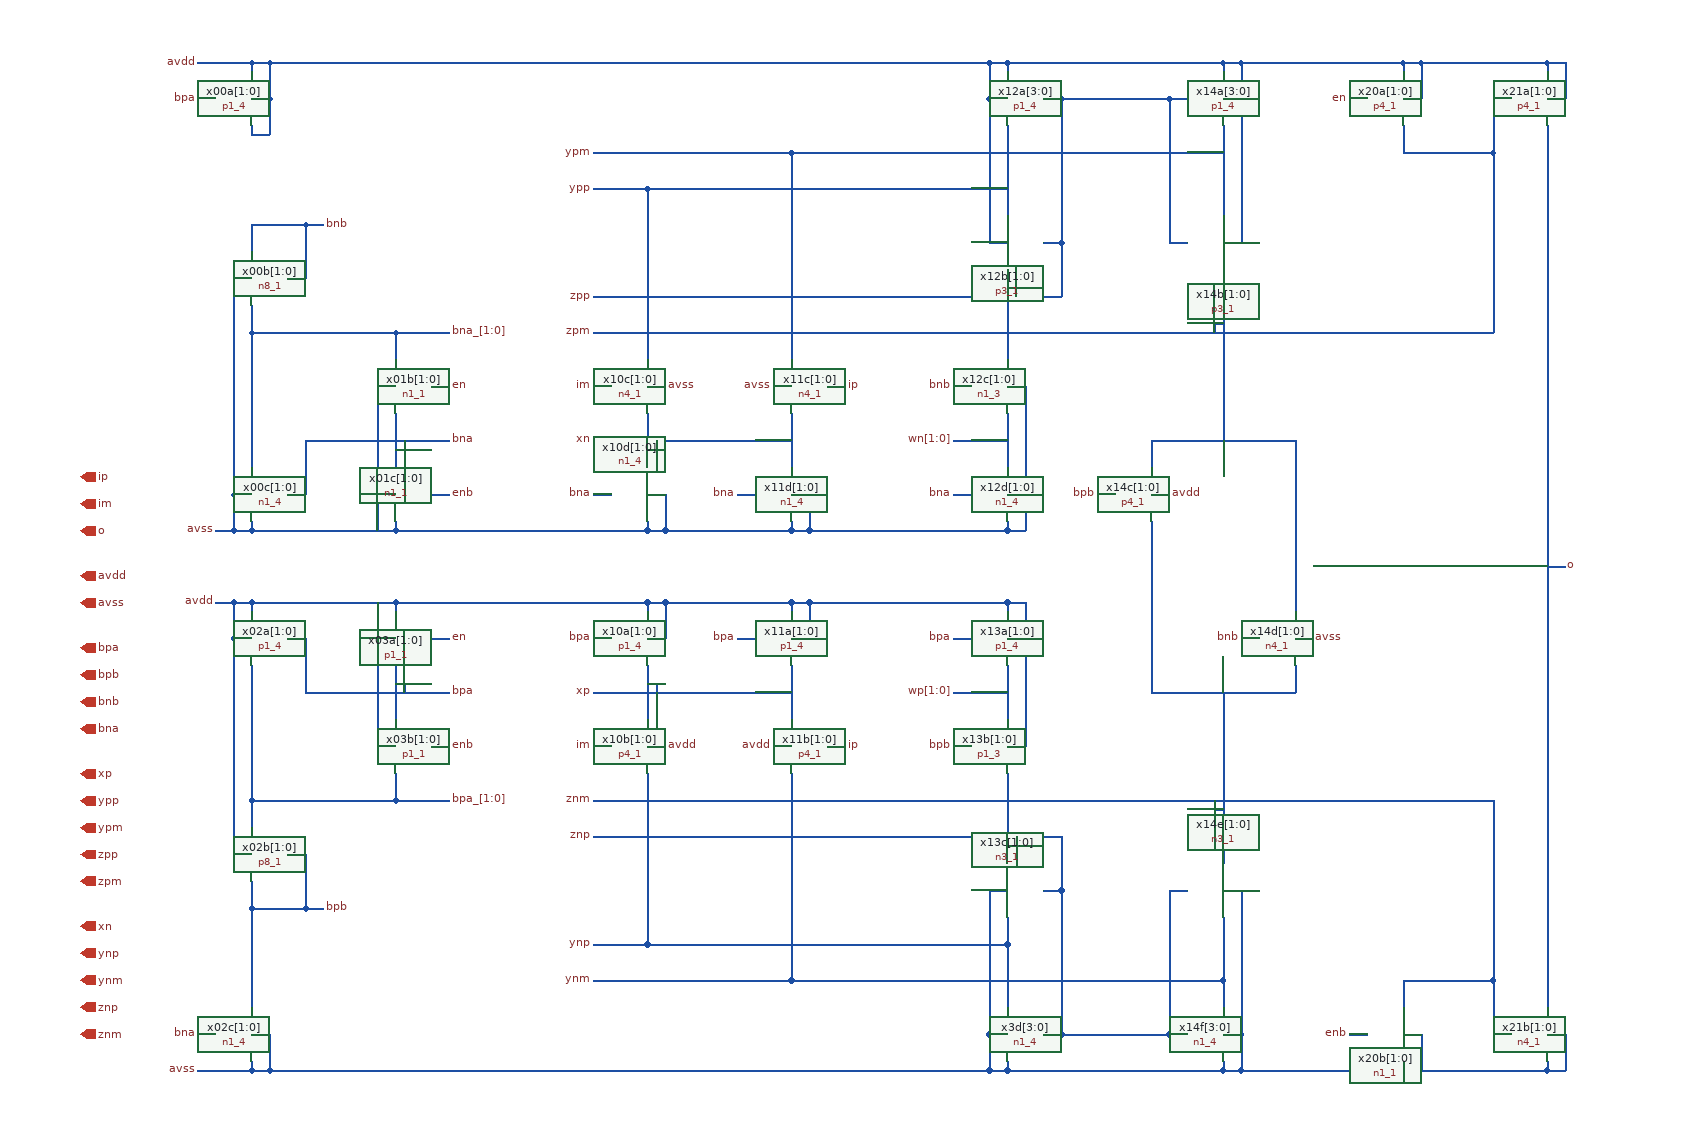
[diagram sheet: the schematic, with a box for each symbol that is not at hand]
v {xschem version=2.9.9 file_version=1.2 }
G {}
K {}
V {}
S {}
E {}
N 220 -760 240 -760 { lab=avss}
N 220 -760 220 -720 { lab=avss}
N 220 -720 240 -720 { lab=avss}
N 240 -730 240 -720 { lab=avss}
N 220 -1000 240 -1000 { lab=avss}
N 240 -1060 240 -1030 { lab=bnb}
N 240 -1060 300 -1060 { lab=bnb}
N 300 -1060 300 -1000 { lab=bnb}
N 280 -1000 300 -1000 { lab=bnb}
N 240 -130 240 -120 { lab=avss}
N 240 -300 300 -300 { lab=bpb}
N 300 -360 300 -300 { lab=bpb}
N 280 -360 300 -360 { lab=bpb}
N 240 -330 240 -300 { lab=bpb}
N 280 -600 300 -600 { lab=bpa}
N 220 -600 240 -600 { lab=avdd}
N 220 -640 220 -600 { lab=avdd}
N 220 -640 240 -640 { lab=avdd}
N 240 -640 240 -630 { lab=avdd}
N 240 -160 260 -160 { lab=avss}
N 260 -160 260 -120 { lab=avss}
N 240 -120 260 -120 { lab=avss}
N 300 -1060 320 -1060 { lab=bnb}
N 300 -300 320 -300 { lab=bpb}
N 220 -360 240 -360 { lab=avdd}
N 200 -640 220 -640 { lab=avdd}
N 200 -720 220 -720 { lab=avss}
N 840 -600 860 -600 { lab=avdd}
N 860 -640 860 -600 { lab=avdd}
N 840 -640 860 -640 { lab=avdd}
N 840 -640 840 -630 { lab=avdd}
N 1140 -380 1140 -320 { lab=znp}
N 1120 -160 1140 -160 { lab=znp}
N 1140 -320 1140 -200 { lab=znp}
N 1120 -320 1140 -320 { lab=znp}
N 1080 -130 1080 -120 { lab=avss}
N 1060 -160 1080 -160 { lab=avss}
N 1060 -160 1060 -120 { lab=avss}
N 1060 -120 1080 -120 { lab=avss}
N 1060 -320 1080 -320 { lab=avss}
N 1140 -200 1140 -160 { lab=znp}
N 1060 -320 1060 -160 { lab=avss}
N 1080 -570 1080 -510 { lab=wp[1:0]}
N 1260 -320 1280 -320 { lab=znp}
N 1320 -320 1340 -320 { lab=avss}
N 1320 -160 1340 -160 { lab=avss}
N 1340 -160 1340 -120 { lab=avss}
N 1320 -120 1340 -120 { lab=avss}
N 1320 -130 1320 -120 { lab=avss}
N 1260 -160 1280 -160 { lab=znp}
N 1340 -320 1340 -160 { lab=avss}
N 1260 -320 1260 -160 { lab=znp}
N 1080 -290 1080 -260 { lab=ynp}
N 1080 -260 1080 -190 { lab=ynp}
N 1080 -450 1080 -350 { lab=znp}
N 680 -450 680 -260 { lab=ynp}
N 840 -450 840 -220 { lab=ynm}
N 1320 -290 1320 -220 { lab=ynm}
N 1320 -220 1320 -190 { lab=ynm}
N 1020 -480 1040 -480 { lab=bpb}
N 1020 -600 1040 -600 { lab=bpa}
N 1080 -480 1100 -480 { lab=avdd}
N 1100 -600 1100 -480 { lab=avdd}
N 1080 -600 1100 -600 { lab=avdd}
N 1100 -640 1100 -600 { lab=avdd}
N 1080 -640 1100 -640 { lab=avdd}
N 1080 -640 1080 -630 { lab=avdd}
N 680 -600 700 -600 { lab=avdd}
N 700 -640 700 -600 { lab=avdd}
N 680 -640 700 -640 { lab=avdd}
N 680 -640 680 -630 { lab=avdd}
N 680 -570 680 -510 { lab=xp}
N 840 -570 840 -510 { lab=xp}
N 700 -640 840 -640 { lab=avdd}
N 620 -600 640 -600 { lab=bpa}
N 780 -600 800 -600 { lab=bpa}
N 620 -540 840 -540 { lab=xp}
N 690 -550 690 -540 { lab=xp}
N 680 -550 690 -550 { lab=xp}
N 820 -480 840 -480 { lab=avdd}
N 680 -480 700 -480 { lab=avdd}
N 680 -730 680 -720 { lab=avss}
N 700 -760 700 -720 { lab=avss}
N 680 -720 700 -720 { lab=avss}
N 680 -760 700 -760 { lab=avss}
N 620 -760 640 -760 { lab=bna}
N 840 -730 840 -720 { lab=avss}
N 860 -760 860 -720 { lab=avss}
N 840 -720 860 -720 { lab=avss}
N 840 -760 860 -760 { lab=avss}
N 780 -760 800 -760 { lab=bna}
N 700 -720 840 -720 { lab=avss}
N 840 -850 840 -790 { lab=xn}
N 680 -850 680 -790 { lab=xn}
N 620 -820 840 -820 { lab=xn}
N 690 -820 690 -810 { lab=xn}
N 680 -810 690 -810 { lab=xn}
N 680 -880 700 -880 { lab=avss}
N 820 -880 840 -880 { lab=avss}
N 1080 -730 1080 -720 { lab=avss}
N 1100 -760 1100 -720 { lab=avss}
N 1080 -720 1100 -720 { lab=avss}
N 1080 -760 1100 -760 { lab=avss}
N 1020 -760 1040 -760 { lab=bna}
N 1080 -880 1100 -880 { lab=avss}
N 1020 -880 1040 -880 { lab=bnb}
N 1100 -880 1100 -760 { lab=avss}
N 1080 -850 1080 -790 { lab=wn[1:0]}
N 1080 -1240 1080 -1230 { lab=avdd}
N 1060 -1240 1080 -1240 { lab=avdd}
N 1060 -1240 1060 -1200 { lab=avdd}
N 1060 -1200 1080 -1200 { lab=avdd}
N 1080 -1170 1080 -1070 { lab=ypp}
N 1060 -1200 1060 -1040 { lab=avdd}
N 1060 -1040 1080 -1040 { lab=avdd}
N 1140 -1040 1140 -980 { lab=zpp}
N 1120 -1040 1140 -1040 { lab=zpp}
N 1140 -1200 1140 -1040 { lab=zpp}
N 1120 -1200 1140 -1200 { lab=zpp}
N 680 -260 1080 -260 { lab=ynp}
N 860 -640 1080 -640 { lab=avdd}
N 860 -720 1080 -720 { lab=avss}
N 1320 -1170 1320 -1070 { lab=ypm}
N 1320 -1040 1340 -1040 { lab=avdd}
N 1340 -1200 1340 -1040 { lab=avdd}
N 1320 -1200 1340 -1200 { lab=avdd}
N 1340 -1240 1340 -1200 { lab=avdd}
N 1320 -1240 1340 -1240 { lab=avdd}
N 1320 -1240 1320 -1230 { lab=avdd}
N 1260 -1040 1280 -1040 { lab=zpp}
N 1260 -1200 1260 -1040 { lab=zpp}
N 1260 -1200 1280 -1200 { lab=zpp}
N 1080 -1010 1080 -910 { lab=zpp}
N 680 -1100 680 -910 { lab=ypp}
N 680 -1100 1080 -1100 { lab=ypp}
N 840 -1140 840 -910 { lab=ypm}
N 1180 -760 1200 -760 { lab=bpb}
N 1340 -600 1360 -600 { lab=bnb}
N 1240 -760 1260 -760 { lab=avdd}
N 1400 -600 1420 -600 { lab=avss}
N 1680 -160 1700 -160 { lab=avss}
N 1700 -160 1700 -120 { lab=avss}
N 1680 -120 1700 -120 { lab=avss}
N 1680 -130 1680 -120 { lab=avss}
N 1680 -1200 1700 -1200 { lab=avdd}
N 1700 -1240 1700 -1200 { lab=avdd}
N 1680 -1240 1700 -1240 { lab=avdd}
N 1680 -1240 1680 -1230 { lab=avdd}
N 840 -220 1320 -220 { lab=ynm}
N 1080 -120 1320 -120 { lab=avss}
N 1240 -540 1400 -540 { lab=znm}
N 1240 -730 1240 -540 { lab=znm}
N 1400 -570 1400 -540 { lab=znm}
N 1240 -820 1240 -790 { lab=zpm}
N 1240 -820 1400 -820 { lab=zpm}
N 1400 -820 1400 -630 { lab=zpm}
N 1320 -1010 1320 -820 { lab=zpm}
N 1320 -540 1320 -350 { lab=znm}
N 1140 -160 1260 -160 { lab=znp}
N 1080 -1240 1320 -1240 { lab=avdd}
N 840 -1140 1320 -1140 { lab=ypm}
N 1680 -1170 1680 -190 { lab=o}
N 1340 -120 1520 -120 { lab=avss}
N 1620 -160 1640 -160 { lab=znm}
N 1310 -420 1310 -410 { lab=znm}
N 1310 -410 1320 -410 { lab=znm}
N 1620 -1200 1640 -1200 { lab=zpm}
N 620 -1140 840 -1140 { lab=ypm}
N 620 -1100 680 -1100 { lab=ypp}
N 620 -220 840 -220 { lab=ynm}
N 620 -260 680 -260 { lab=ynp}
N 1680 -680 1700 -680 { lab=o}
N 880 -480 900 -480 { lab=ip}
N 620 -480 640 -480 { lab=im}
N 880 -880 900 -880 { lab=ip}
N 620 -880 640 -880 { lab=im}
N 620 -380 1140 -380 { lab=znp}
N 1090 -380 1090 -370 { lab=znp}
N 1080 -370 1090 -370 { lab=znp}
N 620 -980 1140 -980 { lab=zpp}
N 1310 -950 1320 -950 { lab=zpm}
N 1310 -950 1310 -940 { lab=zpm}
N 1090 -990 1090 -980 { lab=zpp}
N 1080 -990 1090 -990 { lab=zpp}
N 280 -760 300 -760 { lab=bna}
N 240 -720 400 -720 { lab=avss}
N 300 -820 300 -760 { lab=bna}
N 240 -940 240 -790 { lab=bna_[1:0]}
N 300 -820 460 -820 { lab=bna}
N 400 -850 400 -790 { lab=bna}
N 400 -730 400 -720 { lab=avss}
N 440 -760 460 -760 { lab=enb}
N 440 -880 460 -880 { lab=en}
N 400 -940 400 -910 { lab=bna_[1:0]}
N 380 -880 400 -880 { lab=avss}
N 380 -880 380 -760 { lab=avss}
N 380 -760 400 -760 { lab=avss}
N 380 -760 380 -720 { lab=avss}
N 410 -820 410 -810 { lab=bna}
N 400 -810 410 -810 { lab=bna}
N 220 -1000 220 -760 { lab=avss}
N 240 -970 240 -940 { lab=bna_[1:0]}
N 240 -940 400 -940 { lab=bna_[1:0]}
N 400 -940 460 -940 { lab=bna_[1:0]}
N 1140 -1200 1260 -1200 { lab=zpp}
N 240 -640 400 -640 { lab=avdd}
N 400 -640 400 -630 { lab=avdd}
N 400 -570 400 -510 { lab=bpa}
N 300 -600 300 -540 { lab=bpa}
N 300 -540 460 -540 { lab=bpa}
N 380 -640 380 -600 { lab=avdd}
N 380 -600 400 -600 { lab=avdd}
N 380 -480 400 -480 { lab=avdd}
N 380 -600 380 -480 { lab=avdd}
N 400 -450 400 -420 { lab=bpa_[1:0]}
N 240 -420 400 -420 { lab=bpa_[1:0]}
N 240 -570 240 -420 { lab=bpa_[1:0]}
N 240 -420 240 -390 { lab=bpa_[1:0]}
N 220 -600 220 -360 { lab=avdd}
N 440 -600 460 -600 { lab=en}
N 440 -480 460 -480 { lab=enb}
N 410 -550 410 -540 { lab=bpa}
N 400 -550 410 -550 { lab=bpa}
N 180 -160 200 -160 { lab=bna}
N 400 -420 460 -420 { lab=bpa_[1:0]}
N 1020 -540 1080 -540 { lab=wp[1:0]}
N 1020 -820 1080 -820 { lab=wn[1:0]}
N 240 -300 240 -190 { lab=bpb}
N 180 -120 240 -120 { lab=avss}
N 260 -120 1060 -120 { lab=avss}
N 400 -640 680 -640 { lab=avdd}
N 400 -720 680 -720 { lab=avss}
N 240 -1200 260 -1200 { lab=avdd}
N 260 -1240 260 -1200 { lab=avdd}
N 240 -1240 260 -1240 { lab=avdd}
N 240 -1240 240 -1230 { lab=avdd}
N 180 -1200 200 -1200 { lab=bpa}
N 260 -1200 260 -1160 { lab=avdd}
N 240 -1160 260 -1160 { lab=avdd}
N 240 -1170 240 -1160 { lab=avdd}
N 180 -1240 240 -1240 { lab=avdd}
N 260 -1240 1060 -1240 { lab=avdd}
N 1520 -130 1520 -120 { lab=avss}
N 1520 -120 1680 -120 { lab=avss}
N 1540 -160 1540 -120 { lab=avss}
N 1520 -160 1540 -160 { lab=avss}
N 1520 -220 1520 -190 { lab=znm}
N 1520 -220 1620 -220 { lab=znm}
N 1460 -160 1480 -160 { lab=enb}
N 620 -420 1620 -420 { lab=znm}
N 1460 -1200 1480 -1200 { lab=en}
N 1540 -1240 1680 -1240 { lab=avdd}
N 1540 -1240 1540 -1200 { lab=avdd}
N 1520 -1200 1540 -1200 { lab=avdd}
N 1520 -1240 1520 -1230 { lab=avdd}
N 1520 -1240 1540 -1240 { lab=avdd}
N 1340 -1240 1520 -1240 { lab=avdd}
N 1520 -1170 1520 -1140 { lab=zpm}
N 1520 -1140 1620 -1140 { lab=zpm}
N 1620 -1200 1620 -1140 { lab=zpm}
N 1620 -1140 1620 -940 { lab=zpm}
N 620 -940 1620 -940 { lab=zpm}
N 1620 -220 1620 -160 { lab=znm}
N 1620 -420 1620 -220 { lab=znm}
C {devices/title.sym} 160 -40 0 0 {name=l6 author="Luis Henrique Rodovalho"}
C {devices/iopin.sym} 50 -670 2 1 {name=pavdd lab=avdd}
C {devices/iopin.sym} 50 -640 2 1 {name=pavss lab=avss}
C {devices/iopin.sym} 50 -780 2 1 {name=pip lab=ip}
C {devices/iopin.sym} 50 -750 2 1 {name=pim lab=im}
C {devices/iopin.sym} 50 -720 2 1 {name=po lab=o}
C {n8_1.sym} 260 -1000 0 1 {name=x00b[1:0]}
C {n1_4.sym} 220 -160 0 0 {name=x02c[1:0]}
C {p8_1.sym} 260 -360 0 1 {name=x02b[1:0]}
C {p1_4.sym} 260 -600 0 1 {name=x02a[1:0]}
C {devices/lab_pin.sym} 320 -1060 2 0 {name=l10 sig_type=std_logic lab=bnb}
C {devices/lab_pin.sym} 460 -820 2 0 {name=l11 sig_type=std_logic lab=bna}
C {devices/lab_pin.sym} 320 -300 2 0 {name=l12 sig_type=std_logic lab=bpb}
C {devices/lab_pin.sym} 460 -540 2 0 {name=l13 sig_type=std_logic lab=bpa}
C {devices/lab_pin.sym} 200 -640 2 1 {name=lavdd1 sig_type=std_logic lab=avdd}
C {devices/lab_pin.sym} 200 -720 2 1 {name=lavss0 sig_type=std_logic lab=avss}
C {p4_1.sym} 660 -480 0 0 {name=x10b[1:0]}
C {p1_4.sym} 820 -600 0 0 {name=x11a[1:0]}
C {p4_1.sym} 860 -480 0 1 {name=x11b[1:0]}
C {p1_4.sym} 1060 -600 0 0 {name=x13a[1:0]}
C {n3_1.sym} 1100 -320 0 1 {name=x13c[1:0]}
C {n1_4.sym} 1100 -160 0 1 {name=x3d[3:0]}
C {p1_3.sym} 1060 -480 0 0 {name=x13b[1:0]}
C {n1_4.sym} 1300 -160 0 0 {name=x14f[3:0]}
C {n3_1.sym} 1300 -320 0 0 {name=x14e[1:0]}
C {devices/lab_pin.sym} 1020 -480 2 1 {name=l17 sig_type=std_logic lab=bpb}
C {devices/lab_pin.sym} 1020 -600 2 1 {name=l18 sig_type=std_logic lab=bpa}
C {p1_4.sym} 660 -600 0 0 {name=x10a[1:0]}
C {devices/lab_pin.sym} 620 -600 2 1 {name=l19 sig_type=std_logic lab=bpa}
C {devices/lab_pin.sym} 780 -600 2 1 {name=l20 sig_type=std_logic lab=bpa}
C {devices/lab_pin.sym} 620 -540 2 1 {name=lxp sig_type=std_logic lab=xp}
C {devices/lab_pin.sym} 820 -480 2 1 {name=lavdd3 sig_type=std_logic lab=avdd}
C {devices/lab_pin.sym} 700 -480 2 0 {name=lavdd2 sig_type=std_logic lab=avdd}
C {n1_4.sym} 660 -760 0 0 {name=x10d[1:0]}
C {devices/lab_pin.sym} 620 -760 2 1 {name=l24 sig_type=std_logic lab=bna}
C {n1_4.sym} 820 -760 0 0 {name=x11d[1:0]}
C {devices/lab_pin.sym} 780 -760 2 1 {name=l25 sig_type=std_logic lab=bna}
C {n4_1.sym} 660 -880 0 0 {name=x10c[1:0]}
C {n4_1.sym} 860 -880 0 1 {name=x11c[1:0]}
C {devices/lab_pin.sym} 620 -820 2 1 {name=lxn sig_type=std_logic lab=xn}
C {devices/lab_pin.sym} 700 -880 2 0 {name=lavss2 sig_type=std_logic lab=avss}
C {devices/lab_pin.sym} 820 -880 2 1 {name=lavss3 sig_type=std_logic lab=avss}
C {n1_4.sym} 1060 -760 0 0 {name=x12d[1:0]}
C {devices/lab_pin.sym} 1020 -760 2 1 {name=l29 sig_type=std_logic lab=bna}
C {n1_3.sym} 1060 -880 0 0 {name=x12c[1:0]}
C {devices/lab_pin.sym} 1020 -880 2 1 {name=l30 sig_type=std_logic lab=bnb}
C {p3_1.sym} 1100 -1040 0 1 {name=x12b[1:0]}
C {p1_4.sym} 1100 -1200 0 1 {name=x12a[3:0]}
C {p3_1.sym} 1300 -1040 0 0 {name=x14b[1:0]}
C {p1_4.sym} 1300 -1200 0 0 {name=x14a[3:0]}
C {p4_1.sym} 1220 -760 0 0 {name=x14c[1:0]}
C {devices/lab_pin.sym} 1180 -760 2 1 {name=l31 sig_type=std_logic lab=bpb}
C {n4_1.sym} 1380 -600 0 0 {name=x14d[1:0]}
C {devices/lab_pin.sym} 1340 -600 2 1 {name=l32 sig_type=std_logic lab=bnb}
C {devices/lab_pin.sym} 1260 -760 2 0 {name=lavdd4 sig_type=std_logic lab=avdd}
C {devices/lab_pin.sym} 1420 -600 2 0 {name=lavss4 sig_type=std_logic lab=avss}
C {n4_1.sym} 1660 -160 0 0 {name=x21b[1:0]}
C {p4_1.sym} 1660 -1200 0 0 {name=x21a[1:0]}
C {devices/lab_pin.sym} 180 -120 2 1 {name=lavss1 sig_type=std_logic lab=avss}
C {devices/lab_pin.sym} 180 -1240 2 1 {name=lavdd0 sig_type=std_logic lab=avdd}
C {devices/lab_pin.sym} 1700 -680 2 0 {name=l3 sig_type=std_logic lab=o}
C {devices/lab_pin.sym} 900 -480 2 0 {name=l4 sig_type=std_logic lab=ip}
C {devices/lab_pin.sym} 620 -480 2 1 {name=l5 sig_type=std_logic lab=im}
C {devices/lab_pin.sym} 900 -880 2 0 {name=l7 sig_type=std_logic lab=ip}
C {devices/lab_pin.sym} 620 -880 2 1 {name=l8 sig_type=std_logic lab=im}
C {devices/lab_pin.sym} 620 -220 2 1 {name=lynm sig_type=std_logic lab=ynm}
C {devices/lab_pin.sym} 620 -1100 2 1 {name=lypp sig_type=std_logic lab=ypp}
C {devices/lab_pin.sym} 620 -1140 2 1 {name=lypm sig_type=std_logic lab=ypm}
C {devices/lab_pin.sym} 620 -260 2 1 {name=lynp sig_type=std_logic lab=ynp}
C {devices/lab_pin.sym} 620 -380 2 1 {name=lznm sig_type=std_logic lab=znp}
C {devices/lab_pin.sym} 620 -420 2 1 {name=lznp sig_type=std_logic lab=znm}
C {devices/lab_pin.sym} 620 -940 2 1 {name=lzpp sig_type=std_logic lab=zpm}
C {devices/lab_pin.sym} 620 -980 2 1 {name=lzpm sig_type=std_logic lab=zpp}
C {n1_1.sym} 420 -760 0 1 {name=x01c[1:0]}
C {n1_1.sym} 420 -880 0 1 {name=x01b[1:0]}
C {n1_4.sym} 260 -760 0 1 {name=x00c[1:0]}
C {devices/lab_pin.sym} 460 -760 2 0 {name=l46 sig_type=std_logic lab=enb}
C {devices/lab_pin.sym} 460 -880 2 0 {name=l47 sig_type=std_logic lab=en}
C {devices/lab_pin.sym} 460 -940 2 0 {name=l9 sig_type=std_logic lab=bna_[1:0]}
C {p1_1.sym} 420 -600 0 1 {name=x03a[1:0]}
C {p1_1.sym} 420 -480 0 1 {name=x03b[1:0]}
C {devices/lab_pin.sym} 460 -480 2 0 {name=l48 sig_type=std_logic lab=enb}
C {devices/lab_pin.sym} 460 -600 2 0 {name=l49 sig_type=std_logic lab=en}
C {devices/lab_pin.sym} 180 -160 2 1 {name=l50 sig_type=std_logic lab=bna}
C {devices/lab_pin.sym} 460 -420 2 0 {name=l51 sig_type=std_logic lab=bpa_[1:0]}
C {devices/lab_pin.sym} 1020 -540 2 1 {name=lwp sig_type=std_logic lab=wp[1:0]}
C {devices/lab_pin.sym} 1020 -820 2 1 {name=lwn sig_type=std_logic lab=wn[1:0]}
C {devices/iopin.sym} 50 -590 2 1 {name=pbpa lab=bpa}
C {devices/iopin.sym} 50 -560 2 1 {name=pbpb lab=bpb}
C {devices/iopin.sym} 50 -530 2 1 {name=pbnb lab=bnb}
C {devices/iopin.sym} 50 -500 2 1 {name=pbna lab=bna}
C {devices/iopin.sym} 50 -420 2 1 {name=pypp lab=ypp}
C {devices/iopin.sym} 50 -390 2 1 {name=pypm lab=ypm}
C {devices/iopin.sym} 50 -330 2 1 {name=pzpm lab=zpm}
C {devices/iopin.sym} 50 -360 2 1 {name=pzpp lab=zpp}
C {devices/iopin.sym} 50 -250 2 1 {name=pynp lab=ynp}
C {devices/iopin.sym} 50 -220 2 1 {name=pynm lab=ynm}
C {devices/iopin.sym} 50 -160 2 1 {name=pznm lab=znm}
C {devices/iopin.sym} 50 -190 2 1 {name=pznp lab=znp}
C {p1_4.sym} 220 -1200 0 0 {name=x00a[1:0]}
C {devices/lab_pin.sym} 180 -1200 2 1 {name=l16 sig_type=std_logic lab=bpa}
C {n1_1.sym} 1500 -160 0 0 {name=x20b[1:0]}
C {devices/lab_pin.sym} 1460 -160 2 1 {name=l21 sig_type=std_logic lab=enb}
C {p4_1.sym} 1500 -1200 0 0 {name=x20a[1:0]}
C {devices/lab_pin.sym} 1460 -1200 2 1 {name=l26 sig_type=std_logic lab=en}
C {devices/iopin.sym} 50 -450 2 1 {name=pypp1 lab=xp}
C {devices/iopin.sym} 50 -280 2 1 {name=pynp1 lab=xn}
